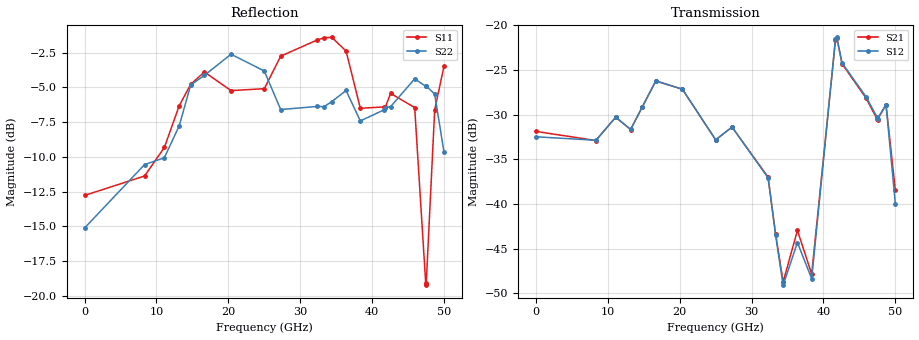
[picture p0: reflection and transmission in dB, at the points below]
!Keysight Technologies,N5245B,MY58422270,A.16.20.02
!Date: Thursday, March 05, 2026 01:44:43
!Correction: S11(C  2-Port  )
!S21(C  2-Port  )
!S12(C  2-Port  )
!S22(C  2-Port  )
!S2P File: Measurements: S11, S21, S12, S22:
# Hz S  dB  R 50
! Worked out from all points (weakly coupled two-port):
!   3201 points, 10 MHz to 50 GHz, reference 50 ohm
!   highest |S21| = -21.40 dB at 41.86 GHz (marker M1); lowest = -48.7 dB at 34.39 GHz (marker M2)
!   lowest |S11| = -19.2 dB at 47.52 GHz (marker M3), VSWR 1.25, Z = 45.1 + j9.21 ohm
!   |S11| at or under -10 dB: start of sweep to 10.03 GHz; 11.36 GHz to 11.93 GHz (573.5 MHz wide, 4.92 % of centre); 46.69 GHz to 48.23 GHz (1.543 GHz wide, 3.25 % of centre)
!   |S22| runs from -19.3 to -2.5 dB; largest |S21 - S12| = 0.0076
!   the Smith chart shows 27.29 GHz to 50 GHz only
!   S11 on the Smith chart (normalised r, x): 27.29 GHz: 0.18, +0.37; 32.3 GHz: 0.42, +1.85; 36.38 GHz: 2.36, -3.33; 42.58 GHz: 0.94, -1.23; 47.45 GHz: 0.86, +0.15; 50 GHz: 0.63, -1.39
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1e7  -12.77 -3.7  -31.89 5.2  -32.49 10.9  -15.11 40.4
8.352081e9  -11.37 174.9  -32.91 33.9  -32.88 33.4  -10.55 -179.4
1.110153e10  -9.32 107.8  -30.29 -58.6  -30.30 -58.7  -10.06 82.7
1.317924e10  -6.31 63.1  -31.69 -109.8  -31.66 -109.6  -7.75 -24.1
1.477267e10  -4.77 12.4  -29.18 -143.3  -29.21 -143.5  -4.82 -91.8
1.667854e10  -3.89 -43.9  -26.23 159.6  -26.24 159.6  -4.13 -142.8
2.038092e10  -5.23 -121.2  -27.17 41.7  -27.16 41.9  -2.61 153.4
2.5005e10  -5.09 -178.9  -32.85 -64.7  -32.81 -65.2  -3.82 71.0
2.728579e10  -2.75 138.7  -31.40 -116.0  -31.41 -117.1  -6.59 31.2
3.230042e10  -1.60 54.9  -37.01 46.8  -37.09 46.1  -6.37 -105.9
3.334708e10  -1.42 36.0  -43.38 0.1  -43.54 1.7  -6.38 -129.9
3.439375e10  -1.40 17.3  -48.75 -91.4  -49.10 -5.7  -6.02 -152.9
3.637772e10  -2.38 -23.0  -42.97 118.0  -44.33 123.6  -5.22 169.1
3.83617e10  -6.50 -22.4  -47.86 78.5  -48.38 130.8  -7.41 137.2
4.167354e10  -6.40 -53.1  -21.61 -54.4  -21.54 -54.5  -6.61 112.3
4.1861e10  -6.38 -53.0  -21.40 -72.5  -21.36 -72.7  -6.47 110.6
4.257961e10  -5.43 -60.5  -24.31 -120.0  -24.22 -119.6  -6.38 107.1
4.592269e10  -6.45 -116.5  -28.16 46.0  -28.01 46.6  -4.38 62.5
4.745363e10  -19.08 127.1  -30.50 -7.3  -30.29 -7.3  -4.92 43.7
4.751612e10  -19.22 112.6  -30.58 -8.2  -30.45 -8.1  -4.89 43.1
4.870338e10  -6.62 -21.3  -28.89 -85.6  -28.90 -86.4  -5.48 20.5
5e10  -3.47 -64.5  -38.49 -134.5  -39.99 -135.7  -9.66 7.0
